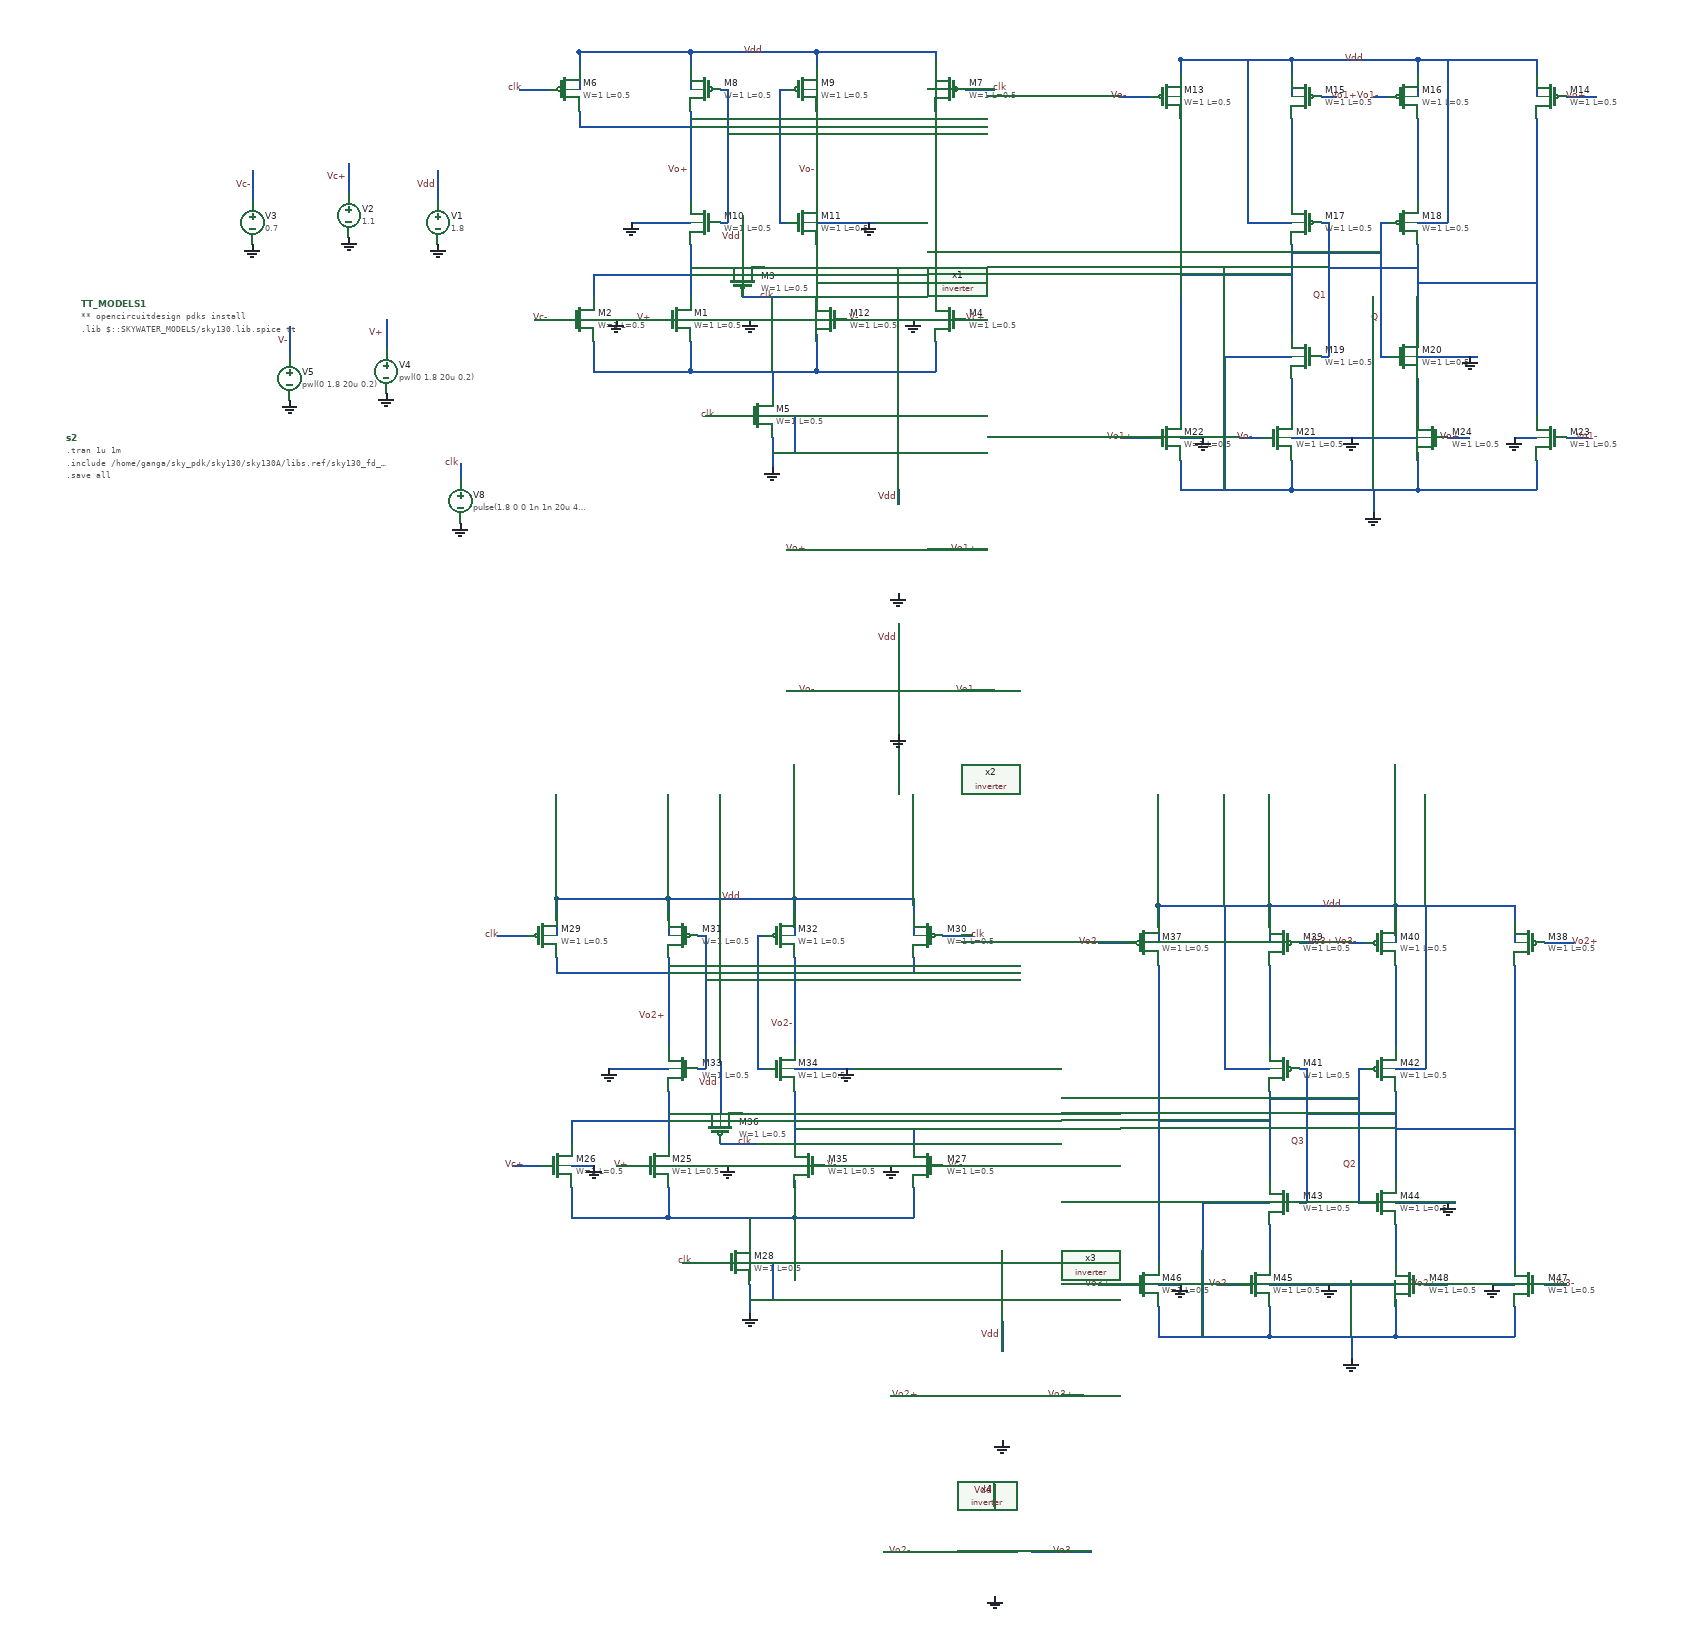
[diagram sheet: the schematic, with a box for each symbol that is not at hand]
v {xschem version=3.4.4 file_version=1.2
}
G {}
K {}
V {}
S {}
E {}
N 90 -250 90 -130 {
lab=Vo+}
N 260 -250 260 -140 {
lab=Vo-}
N 260 -140 260 -130 {
lab=Vo-}
N 90 -330 90 -310 {
lab=Vdd}
N 90 -330 260 -330 {
lab=Vdd}
N 260 -330 260 -310 {
lab=Vdd}
N 130 -280 140 -280 {
lab=Vo-}
N 140 -280 140 -100 {
lab=Vo-}
N 130 -100 140 -100 {
lab=Vo-}
N 210 -280 220 -280 {
lab=Vo+}
N 210 -280 210 -100 {
lab=Vo+}
N 210 -100 220 -100 {
lab=Vo+}
N -60 -330 90 -330 {
lab=Vdd}
N -60 -330 -60 -310 {
lab=Vdd}
N 260 -330 420 -330 {
lab=Vdd}
N 420 -330 420 -310 {
lab=Vdd}
N -60 -250 -60 -230 {
lab=Vo+}
N -60 -230 90 -230 {
lab=Vo+}
N 420 -250 420 -230 {
lab=Vo-}
N 260 -230 420 -230 {
lab=Vo-}
N 90 -240 210 -240 {
lab=Vo+}
N 140 -220 260 -220 {
lab=Vo-}
N 90 -70 90 -0 {
lab=#net1}
N 260 -70 260 0 {
lab=#net2}
N 90 60 90 100 {
lab=#net3}
N 90 100 260 100 {
lab=#net3}
N 260 50 260 100 {
lab=#net3}
N 420 60 420 100 {
lab=#net3}
N 260 100 420 100 {
lab=#net3}
N 420 -20 420 0 {
lab=#net2}
N 260 -20 420 -20 {
lab=#net2}
N -40 60 -40 100 {
lab=#net3}
N -40 100 90 100 {
lab=#net3}
N -40 -30 -40 -0 {
lab=#net1}
N -40 -30 90 -30 {
lab=#net1}
N 200 100 200 130 {
lab=#net3}
N 110 160 160 160 {
lab=clk}
N 200 190 200 230 {
lab=GND}
N 90 -40 130 -40 {
lab=#net1}
N 190 -40 260 -40 {
lab=#net2}
N -120 30 -80 30 {
lab=Vc+}
N 20 30 50 30 {
lab=V+}
N 300 30 330 30 {
lab=V-}
N 460 30 490 30 {
lab=Vc+}
N 460 -280 500 -280 {
lab=clk}
N -140 -280 -100 -280 {
lab=clk}
N 90 30 260 30 {
lab=GND}
N 390 30 420 30 {
lab=GND}
N -40 30 -10 30 {
lab=GND}
N -60 -300 -60 -280 {
lab=Vdd}
N 90 -300 90 -280 {
lab=Vdd}
N 260 -310 260 -290 {
lab=Vdd}
N 260 -300 260 -280 {
lab=Vdd}
N 420 -320 420 -280 {
lab=Vdd}
N 90 -320 90 -280 {
lab=Vdd}
N -60 -330 -60 -280 {
lab=Vdd}
N 260 -100 340 -100 {
lab=GND}
N 10 -100 90 -100 {
lab=GND}
N -250 -170 -250 -130 {
lab=Vdd}
N 160 -110 160 -40 {
lab=Vdd}
N 160 0 210 -0 {
lab=clk}
N -370 -180 -370 -140 {
lab=Vc+}
N -500 -170 -500 -130 {
lab=Vc-}
N -320 30 -320 70 {
lab=V+}
N -450 40 -450 80 {
lab=V-}
N -220 225 -220 245 {
lab=clk}
N 200 160 230 160 {
lab=GND}
N 230 160 230 210 {
lab=GND}
N 200 210 230 210 {
lab=GND}
N 900 -320 900 -300 {
lab=Vdd}
N 900 -320 1070 -320 {
lab=Vdd}
N 1070 -320 1070 -300 {
lab=Vdd}
N 940 -270 950 -270 {
lab=Vo1+}
N 1020 -270 1030 -270 {
lab=Vo1-}
N 750 -320 900 -320 {
lab=Vdd}
N 750 -320 750 -300 {
lab=Vdd}
N 1070 -320 1230 -320 {
lab=Vdd}
N 1230 -320 1230 -300 {
lab=Vdd}
N 750 -240 750 -220 {
lab=Q}
N 1230 -240 1230 -220 {
lab=Q1}
N 1270 -270 1310 -270 {
lab=Vo+}
N 670 -270 710 -270 {
lab=Vo-}
N 750 -290 750 -270 {
lab=Vdd}
N 900 -290 900 -270 {
lab=Vdd}
N 1070 -300 1070 -280 {
lab=Vdd}
N 1070 -290 1070 -270 {
lab=Vdd}
N 1230 -310 1230 -270 {
lab=Vdd}
N 900 -310 900 -270 {
lab=Vdd}
N 750 -320 750 -270 {
lab=Vdd}
N 1070 -240 1070 -150 {
lab=#net4}
N 900 -70 900 50 {
lab=Q}
N 1070 -70 1070 40 {
lab=Q1}
N 1070 40 1070 50 {
lab=Q1}
N 900 -150 900 -130 {
lab=#net5}
N 1070 -150 1070 -130 {
lab=#net4}
N 940 -100 950 -100 {
lab=Q1}
N 950 -100 950 80 {
lab=Q1}
N 940 80 950 80 {
lab=Q1}
N 1020 -100 1030 -100 {
lab=Q}
N 1020 -100 1020 80 {
lab=Q}
N 1020 80 1030 80 {
lab=Q}
N 900 -60 1020 -60 {
lab=Q}
N 950 -40 1070 -40 {
lab=Q1}
N 1070 80 1150 80 {
lab=GND}
N 900 -240 900 -150 {
lab=#net5}
N 900 220 900 260 {
lab=GND}
N 900 260 1070 260 {
lab=GND}
N 1070 210 1070 260 {
lab=GND}
N 1230 220 1230 260 {
lab=GND}
N 1070 260 1230 260 {
lab=GND}
N 1230 140 1230 160 {
lab=Q1}
N 750 220 750 260 {
lab=GND}
N 770 260 900 260 {
lab=GND}
N 750 130 750 160 {
lab=Q}
N 1010 260 1010 290 {
lab=GND}
N 670 190 710 190 {
lab=Vo1+}
N 830 190 860 190 {
lab=Vo-}
N 1110 190 1140 190 {
lab=Vo+}
N 1270 190 1300 190 {
lab=Vo1-}
N 900 190 1070 190 {
lab=GND}
N 1200 190 1230 190 {
lab=GND}
N 750 190 780 190 {
lab=GND}
N 900 110 900 160 {
lab=#net6}
N 1070 110 1070 160 {
lab=#net7}
N 750 -220 750 130 {
lab=Q}
N 1230 -220 1230 130 {
lab=Q1}
N 1230 130 1230 140 {
lab=Q1}
N 750 260 770 260 {
lab=GND}
N 1010 -270 1020 -270 {
lab=Vo1-}
N 950 -270 960 -270 {
lab=Vo1+}
N 750 -30 900 -30 {
lab=Q}
N 1070 -20 1230 -20 {
lab=Q1}
N 220 340 300 340 {
lab=Vo+}
N 430 340 490 340 {
lab=Vo1+}
N 220 530 300 530 {
lab=Vo-}
N 420 530 500 530 {
lab=Vo1-}
N 840 -100 900 -100 {
lab=Vdd}
N 840 -320 840 -100 {
lab=Vdd}
N 1070 -100 1110 -100 {
lab=Vdd}
N 1110 -320 1110 -100 {
lab=Vdd}
N 810 80 900 80 {
lab=GND}
N 810 80 810 260 {
lab=GND}
N 370 260 370 280 {
lab=Vdd}
N 370 440 370 470 {
lab=Vdd}
N 60 890 60 1010 {
lab=Vo2+}
N 230 890 230 1000 {
lab=Vo2-}
N 230 1000 230 1010 {
lab=Vo2-}
N 60 810 60 830 {
lab=Vdd}
N 60 810 230 810 {
lab=Vdd}
N 230 810 230 830 {
lab=Vdd}
N 100 860 110 860 {
lab=Vo2-}
N 110 860 110 1040 {
lab=Vo2-}
N 100 1040 110 1040 {
lab=Vo2-}
N 180 860 190 860 {
lab=Vo2+}
N 180 860 180 1040 {
lab=Vo2+}
N 180 1040 190 1040 {
lab=Vo2+}
N -90 810 60 810 {
lab=Vdd}
N -90 810 -90 830 {
lab=Vdd}
N 230 810 390 810 {
lab=Vdd}
N 390 810 390 830 {
lab=Vdd}
N -90 890 -90 910 {
lab=Vo2+}
N -90 910 60 910 {
lab=Vo2+}
N 390 890 390 910 {
lab=Vo2-}
N 230 910 390 910 {
lab=Vo2-}
N 60 900 180 900 {
lab=Vo2+}
N 110 920 230 920 {
lab=Vo2-}
N 60 1070 60 1140 {
lab=#net8}
N 230 1070 230 1140 {
lab=#net9}
N 60 1200 60 1240 {
lab=#net10}
N 60 1240 230 1240 {
lab=#net10}
N 230 1190 230 1240 {
lab=#net10}
N 390 1200 390 1240 {
lab=#net10}
N 230 1240 390 1240 {
lab=#net10}
N 390 1120 390 1140 {
lab=#net9}
N 230 1120 390 1120 {
lab=#net9}
N -70 1200 -70 1240 {
lab=#net10}
N -70 1240 60 1240 {
lab=#net10}
N -70 1110 -70 1140 {
lab=#net8}
N -70 1110 60 1110 {
lab=#net8}
N 170 1240 170 1270 {
lab=#net10}
N 80 1300 130 1300 {
lab=clk}
N 170 1330 170 1370 {
lab=GND}
N 60 1100 100 1100 {
lab=#net8}
N 160 1100 230 1100 {
lab=#net9}
N -150 1170 -110 1170 {
lab=Vc+}
N -10 1170 20 1170 {
lab=V+}
N 270 1170 300 1170 {
lab=V-}
N 430 1170 460 1170 {
lab=Vc-}
N 430 860 470 860 {
lab=clk}
N -170 860 -130 860 {
lab=clk}
N 60 1170 230 1170 {
lab=GND}
N 360 1170 390 1170 {
lab=GND}
N -70 1170 -40 1170 {
lab=GND}
N -90 840 -90 860 {
lab=Vdd}
N 60 840 60 860 {
lab=Vdd}
N 230 830 230 850 {
lab=Vdd}
N 230 840 230 860 {
lab=Vdd}
N 390 820 390 860 {
lab=Vdd}
N 60 820 60 860 {
lab=Vdd}
N -90 810 -90 860 {
lab=Vdd}
N 230 1040 310 1040 {
lab=GND}
N -20 1040 60 1040 {
lab=GND}
N 130 1030 130 1100 {
lab=Vdd}
N 130 1140 180 1140 {
lab=clk}
N 170 1300 200 1300 {
lab=GND}
N 200 1300 200 1350 {
lab=GND}
N 170 1350 200 1350 {
lab=GND}
N 870 820 870 840 {
lab=Vdd}
N 870 820 1040 820 {
lab=Vdd}
N 1040 820 1040 840 {
lab=Vdd}
N 910 870 920 870 {
lab=Vo3+}
N 990 870 1000 870 {
lab=Vo3-}
N 720 820 870 820 {
lab=Vdd}
N 720 820 720 840 {
lab=Vdd}
N 1040 820 1200 820 {
lab=Vdd}
N 1200 820 1200 840 {
lab=Vdd}
N 720 900 720 920 {
lab=Q2}
N 1200 900 1200 920 {
lab=Q3}
N 1240 870 1280 870 {
lab=Vo2+}
N 640 870 680 870 {
lab=Vo2-}
N 720 850 720 870 {
lab=Vdd}
N 870 850 870 870 {
lab=Vdd}
N 1040 840 1040 860 {
lab=Vdd}
N 1040 850 1040 870 {
lab=Vdd}
N 1200 830 1200 870 {
lab=Vdd}
N 870 830 870 870 {
lab=Vdd}
N 720 820 720 870 {
lab=Vdd}
N 1040 900 1040 990 {
lab=#net11}
N 870 1070 870 1190 {
lab=Q2}
N 1040 1070 1040 1180 {
lab=Q3}
N 1040 1180 1040 1190 {
lab=Q3}
N 870 990 870 1010 {
lab=#net12}
N 1040 990 1040 1010 {
lab=#net11}
N 910 1040 920 1040 {
lab=Q3}
N 920 1040 920 1220 {
lab=Q3}
N 910 1220 920 1220 {
lab=Q3}
N 990 1040 1000 1040 {
lab=Q2}
N 990 1040 990 1220 {
lab=Q2}
N 990 1220 1000 1220 {
lab=Q2}
N 870 1080 990 1080 {
lab=Q2}
N 920 1100 1040 1100 {
lab=Q3}
N 1040 1220 1120 1220 {
lab=GND}
N 870 900 870 990 {
lab=#net12}
N 870 1360 870 1400 {
lab=GND}
N 870 1400 1040 1400 {
lab=GND}
N 1040 1350 1040 1400 {
lab=GND}
N 1200 1360 1200 1400 {
lab=GND}
N 1040 1400 1200 1400 {
lab=GND}
N 1200 1280 1200 1300 {
lab=Q3}
N 720 1360 720 1400 {
lab=GND}
N 740 1400 870 1400 {
lab=GND}
N 720 1270 720 1300 {
lab=Q2}
N 980 1400 980 1430 {
lab=GND}
N 640 1330 680 1330 {
lab=Vo3+}
N 800 1330 830 1330 {
lab=Vo2-}
N 1080 1330 1110 1330 {
lab=Vo2+}
N 1240 1330 1270 1330 {
lab=Vo3-}
N 870 1330 1040 1330 {
lab=GND}
N 1170 1330 1200 1330 {
lab=GND}
N 720 1330 750 1330 {
lab=GND}
N 870 1250 870 1300 {
lab=#net13}
N 1040 1250 1040 1300 {
lab=#net14}
N 720 920 720 1270 {
lab=Q2}
N 1200 920 1200 1270 {
lab=Q3}
N 1200 1270 1200 1280 {
lab=Q3}
N 720 1400 740 1400 {
lab=GND}
N 980 870 990 870 {
lab=Vo3-}
N 920 870 930 870 {
lab=Vo3+}
N 720 1110 870 1110 {
lab=Q2}
N 1040 1120 1200 1120 {
lab=Q3}
N 360 1480 440 1480 {
lab=Vo2+}
N 560 1480 620 1480 {
lab=Vo3+}
N 350 1690 430 1690 {
lab=Vo2-}
N 550 1690 630 1690 {
lab=Vo3-}
N 810 1040 870 1040 {
lab=Vdd}
N 810 820 810 1040 {
lab=Vdd}
N 1040 1040 1080 1040 {
lab=Vdd}
N 1080 820 1080 1040 {
lab=Vdd}
N 780 1220 870 1220 {
lab=GND}
N 780 1220 780 1400 {
lab=GND}
N 510 1380 510 1420 {
lab=Vdd}
N 500 1600 500 1630 {
lab=Vdd}
N 420 340 440 340 {
lab=Vo1+}
C {sky130_fd_pr/nfet_01v8.sym} 70 30 0 0 {name=M1
L=0.5
W=1
nf=1 
mult=1
ad="'int((nf+1)/2) * W/nf * 0.29'" 
pd="'2*int((nf+1)/2) * (W/nf + 0.29)'"
as="'int((nf+2)/2) * W/nf * 0.29'" 
ps="'2*int((nf+2)/2) * (W/nf + 0.29)'"
nrd="'0.29 / W'" nrs="'0.29 / W'"
sa=0 sb=0 sd=0
model=nfet_01v8
spiceprefix=X
}
C {sky130_fd_pr/nfet_01v8.sym} -60 30 0 0 {name=M2
L=0.5
W=1
nf=1 
mult=1
ad="'int((nf+1)/2) * W/nf * 0.29'" 
pd="'2*int((nf+1)/2) * (W/nf + 0.29)'"
as="'int((nf+2)/2) * W/nf * 0.29'" 
ps="'2*int((nf+2)/2) * (W/nf + 0.29)'"
nrd="'0.29 / W'" nrs="'0.29 / W'"
sa=0 sb=0 sd=0
model=nfet_01v8
spiceprefix=X
}
C {sky130_fd_pr/nfet_01v8.sym} 440 30 0 1 {name=M4
L=0.5
W=1
nf=1 
mult=1
ad="'int((nf+1)/2) * W/nf * 0.29'" 
pd="'2*int((nf+1)/2) * (W/nf + 0.29)'"
as="'int((nf+2)/2) * W/nf * 0.29'" 
ps="'2*int((nf+2)/2) * (W/nf + 0.29)'"
nrd="'0.29 / W'" nrs="'0.29 / W'"
sa=0 sb=0 sd=0
model=nfet_01v8
spiceprefix=X
}
C {sky130_fd_pr/nfet_01v8.sym} 180 160 0 0 {name=M5
L=0.5
W=1
nf=1 
mult=1
ad="'int((nf+1)/2) * W/nf * 0.29'" 
pd="'2*int((nf+1)/2) * (W/nf + 0.29)'"
as="'int((nf+2)/2) * W/nf * 0.29'" 
ps="'2*int((nf+2)/2) * (W/nf + 0.29)'"
nrd="'0.29 / W'" nrs="'0.29 / W'"
sa=0 sb=0 sd=0
model=nfet_01v8
spiceprefix=X
}
C {sky130_fd_pr/pfet_01v8.sym} -80 -280 0 0 {name=M6
L=0.5
W=1
nf=1
mult=1
ad="'int((nf+1)/2) * W/nf * 0.29'" 
pd="'2*int((nf+1)/2) * (W/nf + 0.29)'"
as="'int((nf+2)/2) * W/nf * 0.29'" 
ps="'2*int((nf+2)/2) * (W/nf + 0.29)'"
nrd="'0.29 / W'" nrs="'0.29 / W'"
sa=0 sb=0 sd=0
model=pfet_01v8
spiceprefix=X
}
C {sky130_fd_pr/pfet_01v8.sym} 440 -280 0 1 {name=M7
L=0.5
W=1
nf=1
mult=1
ad="'int((nf+1)/2) * W/nf * 0.29'" 
pd="'2*int((nf+1)/2) * (W/nf + 0.29)'"
as="'int((nf+2)/2) * W/nf * 0.29'" 
ps="'2*int((nf+2)/2) * (W/nf + 0.29)'"
nrd="'0.29 / W'" nrs="'0.29 / W'"
sa=0 sb=0 sd=0
model=pfet_01v8
spiceprefix=X
}
C {sky130_fd_pr/pfet_01v8.sym} 110 -280 0 1 {name=M8
L=0.5
W=1
nf=1
mult=1
ad="'int((nf+1)/2) * W/nf * 0.29'" 
pd="'2*int((nf+1)/2) * (W/nf + 0.29)'"
as="'int((nf+2)/2) * W/nf * 0.29'" 
ps="'2*int((nf+2)/2) * (W/nf + 0.29)'"
nrd="'0.29 / W'" nrs="'0.29 / W'"
sa=0 sb=0 sd=0
model=pfet_01v8
spiceprefix=X
}
C {sky130_fd_pr/pfet_01v8.sym} 240 -280 0 0 {name=M9
L=0.5
W=1
nf=1
mult=1
ad="'int((nf+1)/2) * W/nf * 0.29'" 
pd="'2*int((nf+1)/2) * (W/nf + 0.29)'"
as="'int((nf+2)/2) * W/nf * 0.29'" 
ps="'2*int((nf+2)/2) * (W/nf + 0.29)'"
nrd="'0.29 / W'" nrs="'0.29 / W'"
sa=0 sb=0 sd=0
model=pfet_01v8
spiceprefix=X
}
C {sky130_fd_pr/nfet_01v8.sym} 110 -100 0 1 {name=M10
L=0.5
W=1
nf=1 
mult=1
ad="'int((nf+1)/2) * W/nf * 0.29'" 
pd="'2*int((nf+1)/2) * (W/nf + 0.29)'"
as="'int((nf+2)/2) * W/nf * 0.29'" 
ps="'2*int((nf+2)/2) * (W/nf + 0.29)'"
nrd="'0.29 / W'" nrs="'0.29 / W'"
sa=0 sb=0 sd=0
model=nfet_01v8
spiceprefix=X
}
C {sky130_fd_pr/nfet_01v8.sym} 240 -100 0 0 {name=M11
L=0.5
W=1
nf=1 
mult=1
ad="'int((nf+1)/2) * W/nf * 0.29'" 
pd="'2*int((nf+1)/2) * (W/nf + 0.29)'"
as="'int((nf+2)/2) * W/nf * 0.29'" 
ps="'2*int((nf+2)/2) * (W/nf + 0.29)'"
nrd="'0.29 / W'" nrs="'0.29 / W'"
sa=0 sb=0 sd=0
model=nfet_01v8
spiceprefix=X
}
C {sky130_fd_pr/nfet_01v8.sym} 280 30 0 1 {name=M12
L=0.5
W=1
nf=1 
mult=1
ad="'int((nf+1)/2) * W/nf * 0.29'" 
pd="'2*int((nf+1)/2) * (W/nf + 0.29)'"
as="'int((nf+2)/2) * W/nf * 0.29'" 
ps="'2*int((nf+2)/2) * (W/nf + 0.29)'"
nrd="'0.29 / W'" nrs="'0.29 / W'"
sa=0 sb=0 sd=0
model=nfet_01v8
spiceprefix=X
}
C {devices/gnd.sym} 200 230 0 0 {name=l3 lab=GND}
C {devices/gnd.sym} -10 30 0 0 {name=l1 lab=GND}
C {devices/gnd.sym} 170 30 0 0 {name=l2 lab=GND}
C {devices/gnd.sym} 390 30 0 0 {name=l4 lab=GND}
C {devices/gnd.sym} 330 -100 0 0 {name=l5 lab=GND}
C {devices/gnd.sym} 10 -100 0 0 {name=l6 lab=GND}
C {devices/vsource.sym} -250 -100 0 0 {name=V1 value=1.8}
C {devices/gnd.sym} -250 -70 0 0 {name=l8 lab=GND}
C {devices/lab_wire.sym} -250 -150 0 0 {name=p1 sig_type=std_logic lab=Vdd
}
C {devices/lab_wire.sym} 190 -330 0 0 {name=p2 sig_type=std_logic lab=Vdd
}
C {sky130_fd_pr/pfet_01v8.sym} 160 -20 1 1 {name=M3
L=0.5
W=1
nf=1
mult=1
ad="'int((nf+1)/2) * W/nf * 0.29'" 
pd="'2*int((nf+1)/2) * (W/nf + 0.29)'"
as="'int((nf+2)/2) * W/nf * 0.29'" 
ps="'2*int((nf+2)/2) * (W/nf + 0.29)'"
nrd="'0.29 / W'" nrs="'0.29 / W'"
sa=0 sb=0 sd=0
model=pfet_01v8
spiceprefix=X
}
C {devices/lab_wire.sym} 160 -80 1 0 {name=p3 sig_type=std_logic lab=Vdd
}
C {devices/vsource.sym} -370 -110 0 0 {name=V2 value=1.1}
C {devices/gnd.sym} -370 -80 0 0 {name=l7 lab=GND}
C {devices/lab_wire.sym} -370 -160 0 0 {name=p22 sig_type=std_logic lab=Vc+
}
C {devices/vsource.sym} -500 -100 0 0 {name=V3 value=0.7}
C {devices/gnd.sym} -500 -70 0 0 {name=l9 lab=GND}
C {devices/lab_wire.sym} -500 -150 0 0 {name=p4 sig_type=std_logic lab=Vc-
}
C {devices/lab_wire.sym} 490 30 0 0 {name=p5 sig_type=std_logic lab=Vc+
}
C {devices/lab_wire.sym} -100 30 0 0 {name=p6 sig_type=std_logic lab=Vc-
}
C {devices/vsource.sym} -320 100 0 0 {name=V4 value="pwl(0 1.8 20u 0.2)"}
C {devices/gnd.sym} -320 130 0 0 {name=l10 lab=GND}
C {devices/lab_wire.sym} -320 50 0 0 {name=p7 sig_type=std_logic lab=V+
}
C {devices/vsource.sym} -450 110 0 0 {name=V5 value="pwl(0 1.8 20u 0.2)"}
C {devices/gnd.sym} -450 140 0 0 {name=l11 lab=GND}
C {devices/lab_wire.sym} -450 60 0 0 {name=p8 sig_type=std_logic lab=V-
}
C {devices/lab_wire.sym} 40 30 0 0 {name=p9 sig_type=std_logic lab=V+
}
C {devices/lab_wire.sym} 320 30 0 0 {name=p10 sig_type=std_logic lab=V-
}
C {devices/vsource.sym} -220 275 0 0 {name=V8 value="pulse(1.8 0 0 1n 1n 20u 40u)"}
C {devices/gnd.sym} -220 305 0 0 {name=l12 lab=GND}
C {devices/lab_pin.sym} -220 225 1 0 {name=p25 sig_type=std_logic lab=clk
}
C {devices/lab_pin.sym} 125 160 0 0 {name=p11 sig_type=std_logic lab=clk
}
C {devices/lab_pin.sym} 205 0 0 0 {name=p12 sig_type=std_logic lab=clk
}
C {devices/lab_pin.sym} -135 -280 0 0 {name=p13 sig_type=std_logic lab=clk
}
C {devices/lab_pin.sym} 495 -280 0 1 {name=p14 sig_type=std_logic lab=clk
}
C {devices/lab_wire.sym} 90 -170 0 0 {name=p15 sig_type=std_logic lab=Vo+
}
C {devices/lab_wire.sym} 260 -170 0 0 {name=p16 sig_type=std_logic lab=Vo-
}
C {devices/code.sym} -730 10 0 0 {name=TT_MODELS1
only_toplevel=true
format="tcleval( @value )"
value="
** opencircuitdesign pdks install
.lib $::SKYWATER_MODELS/sky130.lib.spice tt

"
spice_ignore=false}
C {devices/code_shown.sym} -750 190 0 0 {name=s2 only_toplevel=false 
value=".tran 1u 1m
.include /home/ganga/sky_pdk/sky130/sky130A/libs.ref/sky130_fd_sc_hd/spice/sky130_fd_sc_hd.spice 
.save all" }
C {sky130_fd_pr/pfet_01v8.sym} 730 -270 0 0 {name=M13
L=0.5
W=1
nf=1
mult=1
ad="'int((nf+1)/2) * W/nf * 0.29'" 
pd="'2*int((nf+1)/2) * (W/nf + 0.29)'"
as="'int((nf+2)/2) * W/nf * 0.29'" 
ps="'2*int((nf+2)/2) * (W/nf + 0.29)'"
nrd="'0.29 / W'" nrs="'0.29 / W'"
sa=0 sb=0 sd=0
model=pfet_01v8
spiceprefix=X
}
C {sky130_fd_pr/pfet_01v8.sym} 1250 -270 0 1 {name=M14
L=0.5
W=1
nf=1
mult=1
ad="'int((nf+1)/2) * W/nf * 0.29'" 
pd="'2*int((nf+1)/2) * (W/nf + 0.29)'"
as="'int((nf+2)/2) * W/nf * 0.29'" 
ps="'2*int((nf+2)/2) * (W/nf + 0.29)'"
nrd="'0.29 / W'" nrs="'0.29 / W'"
sa=0 sb=0 sd=0
model=pfet_01v8
spiceprefix=X
}
C {sky130_fd_pr/pfet_01v8.sym} 920 -270 0 1 {name=M15
L=0.5
W=1
nf=1
mult=1
ad="'int((nf+1)/2) * W/nf * 0.29'" 
pd="'2*int((nf+1)/2) * (W/nf + 0.29)'"
as="'int((nf+2)/2) * W/nf * 0.29'" 
ps="'2*int((nf+2)/2) * (W/nf + 0.29)'"
nrd="'0.29 / W'" nrs="'0.29 / W'"
sa=0 sb=0 sd=0
model=pfet_01v8
spiceprefix=X
}
C {sky130_fd_pr/pfet_01v8.sym} 1050 -270 0 0 {name=M16
L=0.5
W=1
nf=1
mult=1
ad="'int((nf+1)/2) * W/nf * 0.29'" 
pd="'2*int((nf+1)/2) * (W/nf + 0.29)'"
as="'int((nf+2)/2) * W/nf * 0.29'" 
ps="'2*int((nf+2)/2) * (W/nf + 0.29)'"
nrd="'0.29 / W'" nrs="'0.29 / W'"
sa=0 sb=0 sd=0
model=pfet_01v8
spiceprefix=X
}
C {devices/lab_wire.sym} 1000 -320 0 0 {name=p17 sig_type=std_logic lab=Vdd
}
C {sky130_fd_pr/pfet_01v8.sym} 920 -100 0 1 {name=M17
L=0.5
W=1
nf=1
mult=1
ad="'int((nf+1)/2) * W/nf * 0.29'" 
pd="'2*int((nf+1)/2) * (W/nf + 0.29)'"
as="'int((nf+2)/2) * W/nf * 0.29'" 
ps="'2*int((nf+2)/2) * (W/nf + 0.29)'"
nrd="'0.29 / W'" nrs="'0.29 / W'"
sa=0 sb=0 sd=0
model=pfet_01v8
spiceprefix=X
}
C {sky130_fd_pr/pfet_01v8.sym} 1050 -100 0 0 {name=M18
L=0.5
W=1
nf=1
mult=1
ad="'int((nf+1)/2) * W/nf * 0.29'" 
pd="'2*int((nf+1)/2) * (W/nf + 0.29)'"
as="'int((nf+2)/2) * W/nf * 0.29'" 
ps="'2*int((nf+2)/2) * (W/nf + 0.29)'"
nrd="'0.29 / W'" nrs="'0.29 / W'"
sa=0 sb=0 sd=0
model=pfet_01v8
spiceprefix=X
}
C {sky130_fd_pr/nfet_01v8.sym} 920 80 0 1 {name=M19
L=0.5
W=1
nf=1 
mult=1
ad="'int((nf+1)/2) * W/nf * 0.29'" 
pd="'2*int((nf+1)/2) * (W/nf + 0.29)'"
as="'int((nf+2)/2) * W/nf * 0.29'" 
ps="'2*int((nf+2)/2) * (W/nf + 0.29)'"
nrd="'0.29 / W'" nrs="'0.29 / W'"
sa=0 sb=0 sd=0
model=nfet_01v8
spiceprefix=X
}
C {sky130_fd_pr/nfet_01v8.sym} 1050 80 0 0 {name=M20
L=0.5
W=1
nf=1 
mult=1
ad="'int((nf+1)/2) * W/nf * 0.29'" 
pd="'2*int((nf+1)/2) * (W/nf + 0.29)'"
as="'int((nf+2)/2) * W/nf * 0.29'" 
ps="'2*int((nf+2)/2) * (W/nf + 0.29)'"
nrd="'0.29 / W'" nrs="'0.29 / W'"
sa=0 sb=0 sd=0
model=nfet_01v8
spiceprefix=X
}
C {devices/gnd.sym} 1140 80 0 0 {name=l13 lab=GND}
C {sky130_fd_pr/nfet_01v8.sym} 880 190 0 0 {name=M21
L=0.5
W=1
nf=1 
mult=1
ad="'int((nf+1)/2) * W/nf * 0.29'" 
pd="'2*int((nf+1)/2) * (W/nf + 0.29)'"
as="'int((nf+2)/2) * W/nf * 0.29'" 
ps="'2*int((nf+2)/2) * (W/nf + 0.29)'"
nrd="'0.29 / W'" nrs="'0.29 / W'"
sa=0 sb=0 sd=0
model=nfet_01v8
spiceprefix=X
}
C {sky130_fd_pr/nfet_01v8.sym} 730 190 0 0 {name=M22
L=0.5
W=1
nf=1 
mult=1
ad="'int((nf+1)/2) * W/nf * 0.29'" 
pd="'2*int((nf+1)/2) * (W/nf + 0.29)'"
as="'int((nf+2)/2) * W/nf * 0.29'" 
ps="'2*int((nf+2)/2) * (W/nf + 0.29)'"
nrd="'0.29 / W'" nrs="'0.29 / W'"
sa=0 sb=0 sd=0
model=nfet_01v8
spiceprefix=X
}
C {sky130_fd_pr/nfet_01v8.sym} 1250 190 0 1 {name=M23
L=0.5
W=1
nf=1 
mult=1
ad="'int((nf+1)/2) * W/nf * 0.29'" 
pd="'2*int((nf+1)/2) * (W/nf + 0.29)'"
as="'int((nf+2)/2) * W/nf * 0.29'" 
ps="'2*int((nf+2)/2) * (W/nf + 0.29)'"
nrd="'0.29 / W'" nrs="'0.29 / W'"
sa=0 sb=0 sd=0
model=nfet_01v8
spiceprefix=X
}
C {sky130_fd_pr/nfet_01v8.sym} 1090 190 0 1 {name=M24
L=0.5
W=1
nf=1 
mult=1
ad="'int((nf+1)/2) * W/nf * 0.29'" 
pd="'2*int((nf+1)/2) * (W/nf + 0.29)'"
as="'int((nf+2)/2) * W/nf * 0.29'" 
ps="'2*int((nf+2)/2) * (W/nf + 0.29)'"
nrd="'0.29 / W'" nrs="'0.29 / W'"
sa=0 sb=0 sd=0
model=nfet_01v8
spiceprefix=X
}
C {devices/gnd.sym} 780 190 0 0 {name=l14 lab=GND}
C {devices/gnd.sym} 980 190 0 0 {name=l15 lab=GND}
C {devices/gnd.sym} 1200 190 0 0 {name=l16 lab=GND}
C {devices/gnd.sym} 1010 290 0 0 {name=l17 lab=GND}
C {devices/lab_wire.sym} 250 340 0 0 {name=p21 sig_type=std_logic lab=Vo+
}
C {devices/lab_wire.sym} 260 530 0 0 {name=p29 sig_type=std_logic lab=Vo-
}
C {devices/lab_wire.sym} 480 340 0 0 {name=p30 sig_type=std_logic lab=Vo1+
}
C {devices/lab_wire.sym} 480 530 0 0 {name=p31 sig_type=std_logic lab=Vo1-
}
C {devices/lab_wire.sym} 950 -270 0 1 {name=p32 sig_type=std_logic lab=Vo1+
}
C {devices/lab_wire.sym} 1020 -270 0 0 {name=p33 sig_type=std_logic lab=Vo1-
}
C {devices/lab_wire.sym} 690 190 0 0 {name=p20 sig_type=std_logic lab=Vo1+
}
C {devices/lab_wire.sym} 1280 190 0 1 {name=p26 sig_type=std_logic lab=Vo1-
}
C {devices/lab_wire.sym} 950 0 0 0 {name=p34 sig_type=std_logic lab=Q1
}
C {devices/lab_wire.sym} 1020 30 0 0 {name=p35 sig_type=std_logic lab=Q
}
C {inverter.sym} 450 340 0 0 {name=x1}
C {inverter.sym} 450 530 0 0 {name=x2}
C {devices/gnd.sym} 370 400 0 0 {name=l31 lab=GND}
C {devices/lab_wire.sym} 370 270 0 0 {name=p63 sig_type=std_logic lab=Vdd
}
C {devices/lab_wire.sym} 370 460 0 0 {name=p64 sig_type=std_logic lab=Vdd
}
C {devices/gnd.sym} 370 590 0 0 {name=l32 lab=GND}
C {sky130_fd_pr/nfet_01v8.sym} 40 1170 0 0 {name=M25
L=0.5
W=1
nf=1 
mult=1
ad="'int((nf+1)/2) * W/nf * 0.29'" 
pd="'2*int((nf+1)/2) * (W/nf + 0.29)'"
as="'int((nf+2)/2) * W/nf * 0.29'" 
ps="'2*int((nf+2)/2) * (W/nf + 0.29)'"
nrd="'0.29 / W'" nrs="'0.29 / W'"
sa=0 sb=0 sd=0
model=nfet_01v8
spiceprefix=X
}
C {sky130_fd_pr/nfet_01v8.sym} -90 1170 0 0 {name=M26
L=0.5
W=1
nf=1 
mult=1
ad="'int((nf+1)/2) * W/nf * 0.29'" 
pd="'2*int((nf+1)/2) * (W/nf + 0.29)'"
as="'int((nf+2)/2) * W/nf * 0.29'" 
ps="'2*int((nf+2)/2) * (W/nf + 0.29)'"
nrd="'0.29 / W'" nrs="'0.29 / W'"
sa=0 sb=0 sd=0
model=nfet_01v8
spiceprefix=X
}
C {sky130_fd_pr/nfet_01v8.sym} 410 1170 0 1 {name=M27
L=0.5
W=1
nf=1 
mult=1
ad="'int((nf+1)/2) * W/nf * 0.29'" 
pd="'2*int((nf+1)/2) * (W/nf + 0.29)'"
as="'int((nf+2)/2) * W/nf * 0.29'" 
ps="'2*int((nf+2)/2) * (W/nf + 0.29)'"
nrd="'0.29 / W'" nrs="'0.29 / W'"
sa=0 sb=0 sd=0
model=nfet_01v8
spiceprefix=X
}
C {sky130_fd_pr/nfet_01v8.sym} 150 1300 0 0 {name=M28
L=0.5
W=1
nf=1 
mult=1
ad="'int((nf+1)/2) * W/nf * 0.29'" 
pd="'2*int((nf+1)/2) * (W/nf + 0.29)'"
as="'int((nf+2)/2) * W/nf * 0.29'" 
ps="'2*int((nf+2)/2) * (W/nf + 0.29)'"
nrd="'0.29 / W'" nrs="'0.29 / W'"
sa=0 sb=0 sd=0
model=nfet_01v8
spiceprefix=X
}
C {sky130_fd_pr/pfet_01v8.sym} -110 860 0 0 {name=M29
L=0.5
W=1
nf=1
mult=1
ad="'int((nf+1)/2) * W/nf * 0.29'" 
pd="'2*int((nf+1)/2) * (W/nf + 0.29)'"
as="'int((nf+2)/2) * W/nf * 0.29'" 
ps="'2*int((nf+2)/2) * (W/nf + 0.29)'"
nrd="'0.29 / W'" nrs="'0.29 / W'"
sa=0 sb=0 sd=0
model=pfet_01v8
spiceprefix=X
}
C {sky130_fd_pr/pfet_01v8.sym} 410 860 0 1 {name=M30
L=0.5
W=1
nf=1
mult=1
ad="'int((nf+1)/2) * W/nf * 0.29'" 
pd="'2*int((nf+1)/2) * (W/nf + 0.29)'"
as="'int((nf+2)/2) * W/nf * 0.29'" 
ps="'2*int((nf+2)/2) * (W/nf + 0.29)'"
nrd="'0.29 / W'" nrs="'0.29 / W'"
sa=0 sb=0 sd=0
model=pfet_01v8
spiceprefix=X
}
C {sky130_fd_pr/pfet_01v8.sym} 80 860 0 1 {name=M31
L=0.5
W=1
nf=1
mult=1
ad="'int((nf+1)/2) * W/nf * 0.29'" 
pd="'2*int((nf+1)/2) * (W/nf + 0.29)'"
as="'int((nf+2)/2) * W/nf * 0.29'" 
ps="'2*int((nf+2)/2) * (W/nf + 0.29)'"
nrd="'0.29 / W'" nrs="'0.29 / W'"
sa=0 sb=0 sd=0
model=pfet_01v8
spiceprefix=X
}
C {sky130_fd_pr/pfet_01v8.sym} 210 860 0 0 {name=M32
L=0.5
W=1
nf=1
mult=1
ad="'int((nf+1)/2) * W/nf * 0.29'" 
pd="'2*int((nf+1)/2) * (W/nf + 0.29)'"
as="'int((nf+2)/2) * W/nf * 0.29'" 
ps="'2*int((nf+2)/2) * (W/nf + 0.29)'"
nrd="'0.29 / W'" nrs="'0.29 / W'"
sa=0 sb=0 sd=0
model=pfet_01v8
spiceprefix=X
}
C {sky130_fd_pr/nfet_01v8.sym} 80 1040 0 1 {name=M33
L=0.5
W=1
nf=1 
mult=1
ad="'int((nf+1)/2) * W/nf * 0.29'" 
pd="'2*int((nf+1)/2) * (W/nf + 0.29)'"
as="'int((nf+2)/2) * W/nf * 0.29'" 
ps="'2*int((nf+2)/2) * (W/nf + 0.29)'"
nrd="'0.29 / W'" nrs="'0.29 / W'"
sa=0 sb=0 sd=0
model=nfet_01v8
spiceprefix=X
}
C {sky130_fd_pr/nfet_01v8.sym} 210 1040 0 0 {name=M34
L=0.5
W=1
nf=1 
mult=1
ad="'int((nf+1)/2) * W/nf * 0.29'" 
pd="'2*int((nf+1)/2) * (W/nf + 0.29)'"
as="'int((nf+2)/2) * W/nf * 0.29'" 
ps="'2*int((nf+2)/2) * (W/nf + 0.29)'"
nrd="'0.29 / W'" nrs="'0.29 / W'"
sa=0 sb=0 sd=0
model=nfet_01v8
spiceprefix=X
}
C {sky130_fd_pr/nfet_01v8.sym} 250 1170 0 1 {name=M35
L=0.5
W=1
nf=1 
mult=1
ad="'int((nf+1)/2) * W/nf * 0.29'" 
pd="'2*int((nf+1)/2) * (W/nf + 0.29)'"
as="'int((nf+2)/2) * W/nf * 0.29'" 
ps="'2*int((nf+2)/2) * (W/nf + 0.29)'"
nrd="'0.29 / W'" nrs="'0.29 / W'"
sa=0 sb=0 sd=0
model=nfet_01v8
spiceprefix=X
}
C {devices/gnd.sym} 170 1370 0 0 {name=l18 lab=GND}
C {devices/gnd.sym} -40 1170 0 0 {name=l19 lab=GND}
C {devices/gnd.sym} 140 1170 0 0 {name=l20 lab=GND}
C {devices/gnd.sym} 360 1170 0 0 {name=l21 lab=GND}
C {devices/gnd.sym} 300 1040 0 0 {name=l22 lab=GND}
C {devices/gnd.sym} -20 1040 0 0 {name=l23 lab=GND}
C {devices/lab_wire.sym} 160 810 0 0 {name=p27 sig_type=std_logic lab=Vdd
}
C {sky130_fd_pr/pfet_01v8.sym} 130 1120 1 1 {name=M36
L=0.5
W=1
nf=1
mult=1
ad="'int((nf+1)/2) * W/nf * 0.29'" 
pd="'2*int((nf+1)/2) * (W/nf + 0.29)'"
as="'int((nf+2)/2) * W/nf * 0.29'" 
ps="'2*int((nf+2)/2) * (W/nf + 0.29)'"
nrd="'0.29 / W'" nrs="'0.29 / W'"
sa=0 sb=0 sd=0
model=pfet_01v8
spiceprefix=X
}
C {devices/lab_wire.sym} 130 1060 1 0 {name=p36 sig_type=std_logic lab=Vdd
}
C {devices/lab_wire.sym} 460 1170 0 0 {name=p37 sig_type=std_logic lab=Vc-
}
C {devices/lab_wire.sym} -130 1170 0 0 {name=p38 sig_type=std_logic lab=Vc+
}
C {devices/lab_wire.sym} 10 1170 0 0 {name=p39 sig_type=std_logic lab=V+
}
C {devices/lab_wire.sym} 290 1170 0 0 {name=p40 sig_type=std_logic lab=V-
}
C {devices/lab_pin.sym} 95 1300 0 0 {name=p42 sig_type=std_logic lab=clk
}
C {devices/lab_pin.sym} 175 1140 0 0 {name=p43 sig_type=std_logic lab=clk
}
C {devices/lab_pin.sym} -165 860 0 0 {name=p44 sig_type=std_logic lab=clk
}
C {devices/lab_pin.sym} 465 860 0 1 {name=p45 sig_type=std_logic lab=clk
}
C {devices/lab_wire.sym} 60 970 0 0 {name=p46 sig_type=std_logic lab=Vo2+
}
C {devices/lab_wire.sym} 230 980 0 0 {name=p47 sig_type=std_logic lab=Vo2-
}
C {sky130_fd_pr/pfet_01v8.sym} 700 870 0 0 {name=M37
L=0.5
W=1
nf=1
mult=1
ad="'int((nf+1)/2) * W/nf * 0.29'" 
pd="'2*int((nf+1)/2) * (W/nf + 0.29)'"
as="'int((nf+2)/2) * W/nf * 0.29'" 
ps="'2*int((nf+2)/2) * (W/nf + 0.29)'"
nrd="'0.29 / W'" nrs="'0.29 / W'"
sa=0 sb=0 sd=0
model=pfet_01v8
spiceprefix=X
}
C {sky130_fd_pr/pfet_01v8.sym} 1220 870 0 1 {name=M38
L=0.5
W=1
nf=1
mult=1
ad="'int((nf+1)/2) * W/nf * 0.29'" 
pd="'2*int((nf+1)/2) * (W/nf + 0.29)'"
as="'int((nf+2)/2) * W/nf * 0.29'" 
ps="'2*int((nf+2)/2) * (W/nf + 0.29)'"
nrd="'0.29 / W'" nrs="'0.29 / W'"
sa=0 sb=0 sd=0
model=pfet_01v8
spiceprefix=X
}
C {sky130_fd_pr/pfet_01v8.sym} 890 870 0 1 {name=M39
L=0.5
W=1
nf=1
mult=1
ad="'int((nf+1)/2) * W/nf * 0.29'" 
pd="'2*int((nf+1)/2) * (W/nf + 0.29)'"
as="'int((nf+2)/2) * W/nf * 0.29'" 
ps="'2*int((nf+2)/2) * (W/nf + 0.29)'"
nrd="'0.29 / W'" nrs="'0.29 / W'"
sa=0 sb=0 sd=0
model=pfet_01v8
spiceprefix=X
}
C {sky130_fd_pr/pfet_01v8.sym} 1020 870 0 0 {name=M40
L=0.5
W=1
nf=1
mult=1
ad="'int((nf+1)/2) * W/nf * 0.29'" 
pd="'2*int((nf+1)/2) * (W/nf + 0.29)'"
as="'int((nf+2)/2) * W/nf * 0.29'" 
ps="'2*int((nf+2)/2) * (W/nf + 0.29)'"
nrd="'0.29 / W'" nrs="'0.29 / W'"
sa=0 sb=0 sd=0
model=pfet_01v8
spiceprefix=X
}
C {devices/lab_wire.sym} 970 820 0 0 {name=p48 sig_type=std_logic lab=Vdd
}
C {devices/lab_pin.sym} 645 870 0 0 {name=p49 sig_type=std_logic lab=Vo2-
}
C {devices/lab_pin.sym} 1275 870 0 1 {name=p50 sig_type=std_logic lab=Vo2+
}
C {sky130_fd_pr/pfet_01v8.sym} 890 1040 0 1 {name=M41
L=0.5
W=1
nf=1
mult=1
ad="'int((nf+1)/2) * W/nf * 0.29'" 
pd="'2*int((nf+1)/2) * (W/nf + 0.29)'"
as="'int((nf+2)/2) * W/nf * 0.29'" 
ps="'2*int((nf+2)/2) * (W/nf + 0.29)'"
nrd="'0.29 / W'" nrs="'0.29 / W'"
sa=0 sb=0 sd=0
model=pfet_01v8
spiceprefix=X
}
C {sky130_fd_pr/pfet_01v8.sym} 1020 1040 0 0 {name=M42
L=0.5
W=1
nf=1
mult=1
ad="'int((nf+1)/2) * W/nf * 0.29'" 
pd="'2*int((nf+1)/2) * (W/nf + 0.29)'"
as="'int((nf+2)/2) * W/nf * 0.29'" 
ps="'2*int((nf+2)/2) * (W/nf + 0.29)'"
nrd="'0.29 / W'" nrs="'0.29 / W'"
sa=0 sb=0 sd=0
model=pfet_01v8
spiceprefix=X
}
C {sky130_fd_pr/nfet_01v8.sym} 890 1220 0 1 {name=M43
L=0.5
W=1
nf=1 
mult=1
ad="'int((nf+1)/2) * W/nf * 0.29'" 
pd="'2*int((nf+1)/2) * (W/nf + 0.29)'"
as="'int((nf+2)/2) * W/nf * 0.29'" 
ps="'2*int((nf+2)/2) * (W/nf + 0.29)'"
nrd="'0.29 / W'" nrs="'0.29 / W'"
sa=0 sb=0 sd=0
model=nfet_01v8
spiceprefix=X
}
C {sky130_fd_pr/nfet_01v8.sym} 1020 1220 0 0 {name=M44
L=0.5
W=1
nf=1 
mult=1
ad="'int((nf+1)/2) * W/nf * 0.29'" 
pd="'2*int((nf+1)/2) * (W/nf + 0.29)'"
as="'int((nf+2)/2) * W/nf * 0.29'" 
ps="'2*int((nf+2)/2) * (W/nf + 0.29)'"
nrd="'0.29 / W'" nrs="'0.29 / W'"
sa=0 sb=0 sd=0
model=nfet_01v8
spiceprefix=X
}
C {devices/gnd.sym} 1110 1220 0 0 {name=l26 lab=GND}
C {sky130_fd_pr/nfet_01v8.sym} 850 1330 0 0 {name=M45
L=0.5
W=1
nf=1 
mult=1
ad="'int((nf+1)/2) * W/nf * 0.29'" 
pd="'2*int((nf+1)/2) * (W/nf + 0.29)'"
as="'int((nf+2)/2) * W/nf * 0.29'" 
ps="'2*int((nf+2)/2) * (W/nf + 0.29)'"
nrd="'0.29 / W'" nrs="'0.29 / W'"
sa=0 sb=0 sd=0
model=nfet_01v8
spiceprefix=X
}
C {sky130_fd_pr/nfet_01v8.sym} 700 1330 0 0 {name=M46
L=0.5
W=1
nf=1 
mult=1
ad="'int((nf+1)/2) * W/nf * 0.29'" 
pd="'2*int((nf+1)/2) * (W/nf + 0.29)'"
as="'int((nf+2)/2) * W/nf * 0.29'" 
ps="'2*int((nf+2)/2) * (W/nf + 0.29)'"
nrd="'0.29 / W'" nrs="'0.29 / W'"
sa=0 sb=0 sd=0
model=nfet_01v8
spiceprefix=X
}
C {sky130_fd_pr/nfet_01v8.sym} 1220 1330 0 1 {name=M47
L=0.5
W=1
nf=1 
mult=1
ad="'int((nf+1)/2) * W/nf * 0.29'" 
pd="'2*int((nf+1)/2) * (W/nf + 0.29)'"
as="'int((nf+2)/2) * W/nf * 0.29'" 
ps="'2*int((nf+2)/2) * (W/nf + 0.29)'"
nrd="'0.29 / W'" nrs="'0.29 / W'"
sa=0 sb=0 sd=0
model=nfet_01v8
spiceprefix=X
}
C {sky130_fd_pr/nfet_01v8.sym} 1060 1330 0 1 {name=M48
L=0.5
W=1
nf=1 
mult=1
ad="'int((nf+1)/2) * W/nf * 0.29'" 
pd="'2*int((nf+1)/2) * (W/nf + 0.29)'"
as="'int((nf+2)/2) * W/nf * 0.29'" 
ps="'2*int((nf+2)/2) * (W/nf + 0.29)'"
nrd="'0.29 / W'" nrs="'0.29 / W'"
sa=0 sb=0 sd=0
model=nfet_01v8
spiceprefix=X
}
C {devices/gnd.sym} 750 1330 0 0 {name=l27 lab=GND}
C {devices/gnd.sym} 950 1330 0 0 {name=l28 lab=GND}
C {devices/gnd.sym} 1170 1330 0 0 {name=l29 lab=GND}
C {devices/lab_wire.sym} 820 1330 0 0 {name=p51 sig_type=std_logic lab=Vo2-
}
C {devices/lab_wire.sym} 1100 1330 0 0 {name=p52 sig_type=std_logic lab=Vo2+

}
C {devices/gnd.sym} 980 1430 0 0 {name=l30 lab=GND}
C {devices/lab_wire.sym} 400 1480 0 0 {name=p53 sig_type=std_logic lab=Vo2+
}
C {devices/lab_wire.sym} 390 1690 0 0 {name=p54 sig_type=std_logic lab=Vo2-
}
C {devices/lab_wire.sym} 610 1480 0 0 {name=p55 sig_type=std_logic lab=Vo3+
}
C {devices/lab_wire.sym} 610 1690 0 0 {name=p56 sig_type=std_logic lab=Vo3-
}
C {devices/lab_wire.sym} 920 870 0 1 {name=p57 sig_type=std_logic lab=Vo3+
}
C {devices/lab_wire.sym} 990 870 0 0 {name=p58 sig_type=std_logic lab=Vo3-
}
C {devices/lab_wire.sym} 660 1330 0 0 {name=p59 sig_type=std_logic lab=Vo3+
}
C {devices/lab_wire.sym} 1250 1330 0 1 {name=p60 sig_type=std_logic lab=Vo3-
}
C {devices/lab_wire.sym} 920 1140 0 0 {name=p61 sig_type=std_logic lab=Q3
}
C {devices/lab_wire.sym} 990 1170 0 0 {name=p62 sig_type=std_logic lab=Q2
}
C {inverter.sym} 590 1480 0 0 {name=x3}
C {inverter.sym} 580 1690 0 0 {name=x4}
C {devices/gnd.sym} 500 1750 0 0 {name=l24 lab=GND}
C {devices/gnd.sym} 510 1540 0 0 {name=l25 lab=GND}
C {devices/lab_wire.sym} 510 1400 0 0 {name=p24 sig_type=std_logic lab=Vdd
}
C {devices/lab_wire.sym} 500 1610 0 0 {name=p41 sig_type=std_logic lab=Vdd
}
C {devices/lab_wire.sym} 850 190 0 0 {name=p23 sig_type=std_logic lab=Vo-
}
C {devices/lab_wire.sym} 1130 190 0 0 {name=p28 sig_type=std_logic lab=Vo+
}
C {devices/lab_wire.sym} 680 -270 0 0 {name=p18 sig_type=std_logic lab=Vo-
}
C {devices/lab_wire.sym} 1300 -270 0 0 {name=p19 sig_type=std_logic lab=Vo+
}
